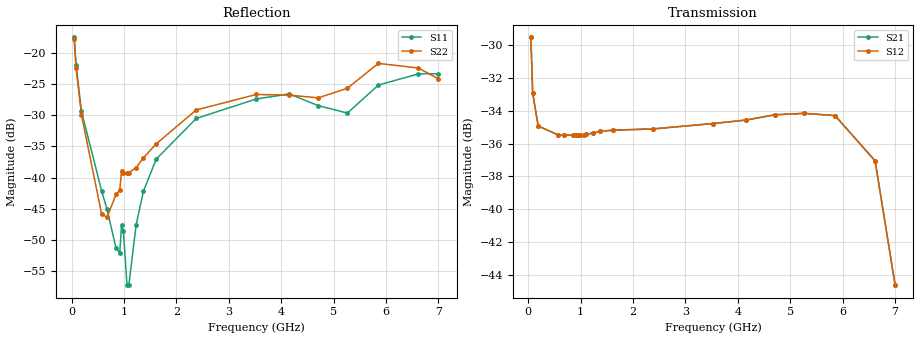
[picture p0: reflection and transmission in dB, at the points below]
! Integrated Device Technology
! Corporate Headquarters
! 6024 Silver Creek Valley Road
! San Jose, CA 95138  USA
! Phone:  1-408-284-8200
! Toll Free:  1-800-223-1366
! Webpage:  http://www.idt.com/
! Timing and RF Division
! 515 Groton Road, Suite 102
! Westford, MA 01886-6024
! Device:  F2258
! Description: Voltage Variable RF Attenuator
! Frequency:  50.0 -  6000.00 MHz
! Package:  3x3 mm Thin QFN Plastic Package: 16 pin
! Ports:  2 RF, 2 DC
!  Pin  1  = NC
!  Pin  2  = NC
!  Pin  3  = RF2  = Port 2
!  Pin  4  = GND
!  Pin  5  = Vdd
!  Pin  6  = NC
!  Pin  7  = VCTRL
!  Pin  8  = NC
!  Pin  9  = GND
!  Pin 10  = RF1  = Port 1
!  Pin 11  = NC
!  Pin 12  = NC
!  Pin 13  = NC
!  Pin 14  = NC
!  Pin 15  = NC
!  Pin 16  = NC
! Vcntrl:  2.400 Volts
! Vdd:  +3.300 Volts
! Current:  1.145 mA
! Data:  The device was measured on a the F2258 evaluation board which has
!  individual transmission lines to the RF pins.  Data was collected
!  using a calibrated network analyzer.  The evaluation board was
!  de-embedded using a TRL calibration technique.
!  The reference plane is the edge of the package pin.
! Misc:  SN 10
!  Action Tracker AT0285
! Date Measured:  2014-12-10
! Date:  2016-01-13  MJV
! Note:
!  Integrated Device Technology supplies this data as a sample of measured
!  data at the package pin for this product.  Your particular data for this
!  product may vary.
!  Data was taken at 25 degrees C.
!  Integrated Device Technology reserves the right to change this data at anytime.
!Freq_(GHz)  S11M_(dB)  S11P_(deg)  S21M_(dB)  S21P_(deg)  S12M_(dB)  S12P_(deg)  S22M_(dB)  S22P_(deg)
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# GHz S dB R 50
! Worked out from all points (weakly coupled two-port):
!   201 points, 50 MHz to 7 GHz, reference 50 ohm
!   highest |S21| = -29.54 dB at 50 MHz (marker M1); lowest = -44.6 dB at 7 GHz (marker M2)
!   lowest |S11| = -57.2 dB at 1.093 GHz (marker M3), VSWR 1.00, Z = 49.9 + j0.115 ohm
!   |S11| at or under -10 dB: start of sweep to end of sweep
!   |S22| runs from -46.4 to -17.8 dB; largest |S21 - S12| = 7e-05
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0.05  -17.56 -111.0  -29.54 -68.7  -29.54 -68.7  -17.77 -111.7
0.08475  -21.97 -107.4  -32.92 -48.9  -32.92 -48.9  -22.40 -108.4
0.189  -29.41 -109.4  -34.93 -24.8  -34.93 -24.8  -29.96 -112.2
0.57125  -42.06 -125.2  -35.47 -10.3  -35.48 -10.3  -45.74 -170.2
0.6755  -45.03 -132.3  -35.49 -9.4  -35.49 -9.4  -46.37 153.5
0.84925  -51.31 -174.6  -35.49 -8.5  -35.49 -8.5  -42.65 127.6
0.91875  -52.09 151.1  -35.48 -8.3  -35.48 -8.3  -42.03 124.2
0.9535  -47.59 -163.4  -35.49 -8.2  -35.49 -8.2  -38.92 127.6
0.98825  -48.53 -174.7  -35.47 -8.1  -35.47 -8.0  -39.21 125.7
1.05775  -57.18 151.6  -35.45 -7.9  -35.46 -7.9  -39.33 112.0
1.0925  -57.19 123.8  -35.44 -7.8  -35.44 -7.9  -39.19 108.3
1.2315  -47.55 46.9  -35.36 -7.8  -35.36 -7.8  -38.42 86.7
1.3705  -42.19 37.4  -35.26 -8.3  -35.25 -8.2  -36.82 72.7
1.61375  -37.04 32.9  -35.18 -9.5  -35.19 -9.5  -34.60 57.9
2.37825  -30.53 48.1  -35.11 -13.1  -35.11 -13.1  -29.17 45.9
3.525  -27.41 91.6  -34.78 -19.4  -34.78 -19.4  -26.69 69.1
4.1505  -26.61 105.0  -34.57 -23.8  -34.57 -23.8  -26.80 76.4
4.7065  -28.47 95.7  -34.25 -28.5  -34.25 -28.6  -27.23 60.2
5.2625  -29.67 54.3  -34.16 -34.7  -34.16 -34.7  -25.70 22.9
5.85325  -25.19 29.9  -34.30 -45.3  -34.30 -45.3  -21.72 -1.5
6.61775  -23.40 49.7  -37.04 -68.6  -37.06 -68.5  -22.46 -43.4
7  -23.37 84.5  -44.61 -61.4  -44.61 -61.1  -24.20 -130.2
